VERSION 5.7 ;
  NOWIREEXTENSIONATPIN ON ;
  DIVIDERCHAR "/" ;
  BUSBITCHARS "[]" ;
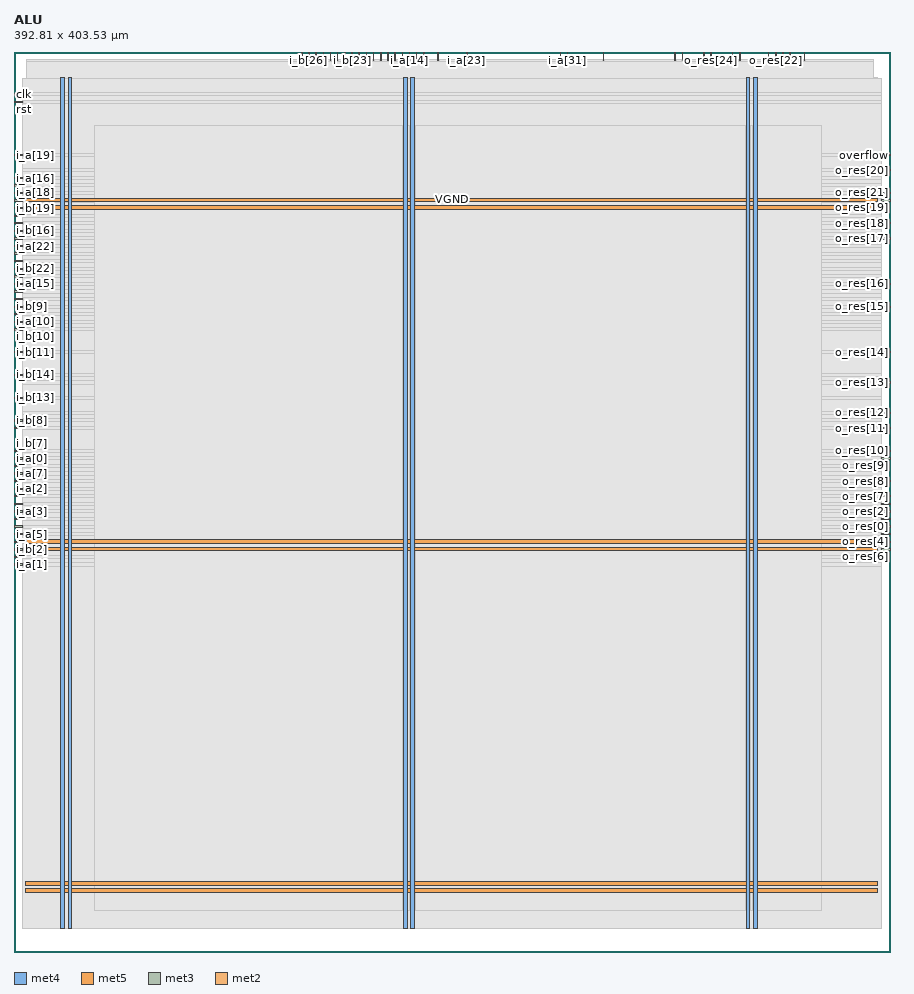
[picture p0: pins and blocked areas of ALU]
MACRO ALU
  CLASS BLOCK ;
  FOREIGN ALU ;
  ORIGIN 0.000 0.000 ;
  SIZE 392.810 BY 403.530 ;
  PIN VGND
    DIRECTION INOUT ;
    USE GROUND ;
    PORT
      LAYER met4 ;
        RECT 24.340 10.640 25.940 391.920 ;
    END
    PORT
      LAYER met4 ;
        RECT 177.940 10.640 179.540 391.920 ;
    END
    PORT
      LAYER met4 ;
        RECT 331.540 10.640 333.140 391.920 ;
    END
    PORT
      LAYER met5 ;
        RECT 5.280 30.030 387.100 31.630 ;
    END
    PORT
      LAYER met5 ;
        RECT 5.280 183.210 387.100 184.810 ;
    END
    PORT
      LAYER met5 ;
        RECT 5.280 336.390 387.100 337.990 ;
    END
  END VGND
  PIN VPWR
    DIRECTION INOUT ;
    USE POWER ;
    PORT
      LAYER met4 ;
        RECT 21.040 10.640 22.640 391.920 ;
    END
    PORT
      LAYER met4 ;
        RECT 174.640 10.640 176.240 391.920 ;
    END
    PORT
      LAYER met4 ;
        RECT 328.240 10.640 329.840 391.920 ;
    END
    PORT
      LAYER met5 ;
        RECT 5.280 26.730 387.100 28.330 ;
    END
    PORT
      LAYER met5 ;
        RECT 5.280 179.910 387.100 181.510 ;
    END
    PORT
      LAYER met5 ;
        RECT 5.280 333.090 387.100 334.690 ;
    END
  END VPWR
  PIN clk
    DIRECTION INPUT ;
    USE SIGNAL ;
    ANTENNAGATEAREA 1.286700 ;
    ANTENNADIFFAREA 0.434700 ;
    PORT
      LAYER met3 ;
        RECT 0.000 384.240 4.000 384.840 ;
    END
  END clk
  PIN i_a[0]
    DIRECTION INPUT ;
    USE SIGNAL ;
    ANTENNAGATEAREA 0.631200 ;
    ANTENNADIFFAREA 0.434700 ;
    PORT
      LAYER met3 ;
        RECT 0.000 221.040 4.000 221.640 ;
    END
  END i_a[0]
  PIN i_a[10]
    DIRECTION INPUT ;
    USE SIGNAL ;
    ANTENNAGATEAREA 0.631200 ;
    ANTENNADIFFAREA 0.434700 ;
    PORT
      LAYER met3 ;
        RECT 0.000 282.240 4.000 282.840 ;
    END
  END i_a[10]
  PIN i_a[11]
    DIRECTION INPUT ;
    USE SIGNAL ;
    ANTENNAGATEAREA 0.631200 ;
    ANTENNADIFFAREA 0.434700 ;
    PORT
      LAYER met2 ;
        RECT 128.890 399.530 129.170 403.530 ;
    END
  END i_a[11]
  PIN i_a[12]
    DIRECTION INPUT ;
    USE SIGNAL ;
    ANTENNAGATEAREA 0.631200 ;
    ANTENNADIFFAREA 0.434700 ;
    PORT
      LAYER met3 ;
        RECT 0.000 285.640 4.000 286.240 ;
    END
  END i_a[12]
  PIN i_a[13]
    DIRECTION INPUT ;
    USE SIGNAL ;
    ANTENNAGATEAREA 0.631200 ;
    ANTENNADIFFAREA 0.434700 ;
    PORT
      LAYER met2 ;
        RECT 135.330 399.530 135.610 403.530 ;
    END
  END i_a[13]
  PIN i_a[14]
    DIRECTION INPUT ;
    USE SIGNAL ;
    ANTENNAGATEAREA 0.631200 ;
    ANTENNADIFFAREA 0.434700 ;
    PORT
      LAYER met2 ;
        RECT 177.190 399.530 177.470 403.530 ;
    END
  END i_a[14]
  PIN i_a[15]
    DIRECTION INPUT ;
    USE SIGNAL ;
    ANTENNAGATEAREA 0.631200 ;
    ANTENNADIFFAREA 0.434700 ;
    PORT
      LAYER met3 ;
        RECT 0.000 299.240 4.000 299.840 ;
    END
  END i_a[15]
  PIN i_a[16]
    DIRECTION INPUT ;
    USE SIGNAL ;
    ANTENNAGATEAREA 0.631200 ;
    ANTENNADIFFAREA 0.434700 ;
    PORT
      LAYER met3 ;
        RECT 0.000 343.440 4.000 344.040 ;
    END
  END i_a[16]
  PIN i_a[17]
    DIRECTION INPUT ;
    USE SIGNAL ;
    ANTENNAGATEAREA 0.631200 ;
    ANTENNADIFFAREA 0.434700 ;
    PORT
      LAYER met3 ;
        RECT 0.000 329.840 4.000 330.440 ;
    END
  END i_a[17]
  PIN i_a[18]
    DIRECTION INPUT ;
    USE SIGNAL ;
    ANTENNAGATEAREA 0.631200 ;
    ANTENNADIFFAREA 0.434700 ;
    PORT
      LAYER met3 ;
        RECT 0.000 340.040 4.000 340.640 ;
    END
  END i_a[18]
  PIN i_a[19]
    DIRECTION INPUT ;
    USE SIGNAL ;
    ANTENNAGATEAREA 0.631200 ;
    ANTENNADIFFAREA 0.434700 ;
    PORT
      LAYER met3 ;
        RECT 0.000 357.040 4.000 357.640 ;
    END
  END i_a[19]
  PIN i_a[1]
    DIRECTION INPUT ;
    USE SIGNAL ;
    ANTENNAGATEAREA 0.631200 ;
    ANTENNADIFFAREA 0.434700 ;
    PORT
      LAYER met3 ;
        RECT 0.000 173.440 4.000 174.040 ;
    END
  END i_a[1]
  PIN i_a[20]
    DIRECTION INPUT ;
    USE SIGNAL ;
    ANTENNAGATEAREA 0.631200 ;
    ANTENNADIFFAREA 0.434700 ;
    PORT
      LAYER met3 ;
        RECT 0.000 346.840 4.000 347.440 ;
    END
  END i_a[20]
  PIN i_a[21]
    DIRECTION INPUT ;
    USE SIGNAL ;
    ANTENNAGATEAREA 0.631200 ;
    ANTENNADIFFAREA 0.434700 ;
    PORT
      LAYER met3 ;
        RECT 0.000 326.440 4.000 327.040 ;
    END
  END i_a[21]
  PIN i_a[22]
    DIRECTION INPUT ;
    USE SIGNAL ;
    ANTENNAGATEAREA 0.631200 ;
    ANTENNADIFFAREA 0.434700 ;
    PORT
      LAYER met3 ;
        RECT 0.000 316.240 4.000 316.840 ;
    END
  END i_a[22]
  PIN i_a[23]
    DIRECTION INPUT ;
    USE SIGNAL ;
    ANTENNAGATEAREA 0.631200 ;
    ANTENNADIFFAREA 0.434700 ;
    PORT
      LAYER met2 ;
        RECT 202.950 399.530 203.230 403.530 ;
    END
  END i_a[23]
  PIN i_a[24]
    DIRECTION INPUT ;
    USE SIGNAL ;
    ANTENNAGATEAREA 0.631200 ;
    ANTENNADIFFAREA 0.434700 ;
    PORT
      LAYER met2 ;
        RECT 190.070 399.530 190.350 403.530 ;
    END
  END i_a[24]
  PIN i_a[25]
    DIRECTION INPUT ;
    USE SIGNAL ;
    ANTENNAGATEAREA 0.631200 ;
    ANTENNADIFFAREA 0.434700 ;
    PORT
      LAYER met2 ;
        RECT 180.410 399.530 180.690 403.530 ;
    END
  END i_a[25]
  PIN i_a[26]
    DIRECTION INPUT ;
    USE SIGNAL ;
    ANTENNAGATEAREA 0.631200 ;
    ANTENNADIFFAREA 0.434700 ;
    PORT
      LAYER met2 ;
        RECT 183.630 399.530 183.910 403.530 ;
    END
  END i_a[26]
  PIN i_a[27]
    DIRECTION INPUT ;
    USE SIGNAL ;
    ANTENNAGATEAREA 0.631200 ;
    ANTENNADIFFAREA 0.434700 ;
    PORT
      LAYER met2 ;
        RECT 164.310 399.530 164.590 403.530 ;
    END
  END i_a[27]
  PIN i_a[28]
    DIRECTION INPUT ;
    USE SIGNAL ;
    ANTENNAGATEAREA 0.631200 ;
    ANTENNADIFFAREA 0.434700 ;
    PORT
      LAYER met2 ;
        RECT 173.970 399.530 174.250 403.530 ;
    END
  END i_a[28]
  PIN i_a[29]
    DIRECTION INPUT ;
    USE SIGNAL ;
    ANTENNAGATEAREA 0.631200 ;
    ANTENNADIFFAREA 0.434700 ;
    PORT
      LAYER met2 ;
        RECT 161.090 399.530 161.370 403.530 ;
    END
  END i_a[29]
  PIN i_a[2]
    DIRECTION INPUT ;
    USE SIGNAL ;
    ANTENNAGATEAREA 0.631200 ;
    ANTENNADIFFAREA 0.434700 ;
    PORT
      LAYER met3 ;
        RECT 0.000 207.440 4.000 208.040 ;
    END
  END i_a[2]
  PIN i_a[30]
    DIRECTION INPUT ;
    USE SIGNAL ;
    ANTENNAGATEAREA 0.631200 ;
    ANTENNADIFFAREA 0.434700 ;
    PORT
      LAYER met2 ;
        RECT 138.550 399.530 138.830 403.530 ;
    END
  END i_a[30]
  PIN i_a[31]
    DIRECTION INPUT ;
    USE SIGNAL ;
    ANTENNAGATEAREA 0.631200 ;
    ANTENNADIFFAREA 0.434700 ;
    PORT
      LAYER met2 ;
        RECT 248.030 399.530 248.310 403.530 ;
    END
  END i_a[31]
  PIN i_a[3]
    DIRECTION INPUT ;
    USE SIGNAL ;
    ANTENNAGATEAREA 0.631200 ;
    ANTENNADIFFAREA 0.434700 ;
    PORT
      LAYER met3 ;
        RECT 0.000 197.240 4.000 197.840 ;
    END
  END i_a[3]
  PIN i_a[4]
    DIRECTION INPUT ;
    USE SIGNAL ;
    ANTENNAGATEAREA 0.631200 ;
    ANTENNADIFFAREA 0.434700 ;
    PORT
      LAYER met3 ;
        RECT 0.000 183.640 4.000 184.240 ;
    END
  END i_a[4]
  PIN i_a[5]
    DIRECTION INPUT ;
    USE SIGNAL ;
    ANTENNAGATEAREA 0.631200 ;
    ANTENNADIFFAREA 0.434700 ;
    PORT
      LAYER met3 ;
        RECT 0.000 187.040 4.000 187.640 ;
    END
  END i_a[5]
  PIN i_a[6]
    DIRECTION INPUT ;
    USE SIGNAL ;
    ANTENNAGATEAREA 0.631200 ;
    ANTENNADIFFAREA 0.434700 ;
    PORT
      LAYER met3 ;
        RECT 0.000 193.840 4.000 194.440 ;
    END
  END i_a[6]
  PIN i_a[7]
    DIRECTION INPUT ;
    USE SIGNAL ;
    ANTENNAGATEAREA 0.631200 ;
    ANTENNADIFFAREA 0.434700 ;
    PORT
      LAYER met3 ;
        RECT 0.000 210.840 4.000 211.440 ;
    END
  END i_a[7]
  PIN i_a[8]
    DIRECTION INPUT ;
    USE SIGNAL ;
    ANTENNAGATEAREA 0.631200 ;
    ANTENNADIFFAREA 0.434700 ;
    PORT
      LAYER met3 ;
        RECT 0.000 234.640 4.000 235.240 ;
    END
  END i_a[8]
  PIN i_a[9]
    DIRECTION INPUT ;
    USE SIGNAL ;
    ANTENNAGATEAREA 0.631200 ;
    ANTENNADIFFAREA 0.434700 ;
    PORT
      LAYER met3 ;
        RECT 0.000 295.840 4.000 296.440 ;
    END
  END i_a[9]
  PIN i_b[0]
    DIRECTION INPUT ;
    USE SIGNAL ;
    ANTENNAGATEAREA 0.631200 ;
    ANTENNADIFFAREA 0.434700 ;
    PORT
      LAYER met3 ;
        RECT 0.000 217.640 4.000 218.240 ;
    END
  END i_b[0]
  PIN i_b[10]
    DIRECTION INPUT ;
    USE SIGNAL ;
    ANTENNAGATEAREA 0.631200 ;
    ANTENNADIFFAREA 0.434700 ;
    PORT
      LAYER met3 ;
        RECT 0.000 278.840 4.000 279.440 ;
    END
  END i_b[10]
  PIN i_b[11]
    DIRECTION INPUT ;
    USE SIGNAL ;
    ANTENNAGATEAREA 0.631200 ;
    ANTENNADIFFAREA 0.434700 ;
    PORT
      LAYER met3 ;
        RECT 0.000 268.640 4.000 269.240 ;
    END
  END i_b[11]
  PIN i_b[12]
    DIRECTION INPUT ;
    USE SIGNAL ;
    ANTENNAGATEAREA 0.631200 ;
    ANTENNADIFFAREA 0.434700 ;
    PORT
      LAYER met3 ;
        RECT 0.000 292.440 4.000 293.040 ;
    END
  END i_b[12]
  PIN i_b[13]
    DIRECTION INPUT ;
    USE SIGNAL ;
    ANTENNAGATEAREA 0.631200 ;
    ANTENNADIFFAREA 0.434700 ;
    PORT
      LAYER met3 ;
        RECT 0.000 248.240 4.000 248.840 ;
    END
  END i_b[13]
  PIN i_b[14]
    DIRECTION INPUT ;
    USE SIGNAL ;
    ANTENNAGATEAREA 0.631200 ;
    ANTENNADIFFAREA 0.434700 ;
    PORT
      LAYER met3 ;
        RECT 0.000 258.440 4.000 259.040 ;
    END
  END i_b[14]
  PIN i_b[15]
    DIRECTION INPUT ;
    USE SIGNAL ;
    ANTENNAGATEAREA 0.631200 ;
    ANTENNADIFFAREA 0.434700 ;
    PORT
      LAYER met3 ;
        RECT 0.000 302.640 4.000 303.240 ;
    END
  END i_b[15]
  PIN i_b[16]
    DIRECTION INPUT ;
    USE SIGNAL ;
    ANTENNAGATEAREA 0.631200 ;
    ANTENNADIFFAREA 0.434700 ;
    PORT
      LAYER met3 ;
        RECT 0.000 323.040 4.000 323.640 ;
    END
  END i_b[16]
  PIN i_b[17]
    DIRECTION INPUT ;
    USE SIGNAL ;
    ANTENNAGATEAREA 0.631200 ;
    ANTENNADIFFAREA 0.434700 ;
    PORT
      LAYER met3 ;
        RECT 0.000 312.840 4.000 313.440 ;
    END
  END i_b[17]
  PIN i_b[18]
    DIRECTION INPUT ;
    USE SIGNAL ;
    ANTENNAGATEAREA 0.631200 ;
    ANTENNADIFFAREA 0.434700 ;
    PORT
      LAYER met3 ;
        RECT 0.000 319.640 4.000 320.240 ;
    END
  END i_b[18]
  PIN i_b[19]
    DIRECTION INPUT ;
    USE SIGNAL ;
    ANTENNAGATEAREA 0.631200 ;
    ANTENNADIFFAREA 0.434700 ;
    PORT
      LAYER met3 ;
        RECT 0.000 333.240 4.000 333.840 ;
    END
  END i_b[19]
  PIN i_b[1]
    DIRECTION INPUT ;
    USE SIGNAL ;
    ANTENNAGATEAREA 0.631200 ;
    ANTENNADIFFAREA 0.434700 ;
    PORT
      LAYER met3 ;
        RECT 0.000 200.640 4.000 201.240 ;
    END
  END i_b[1]
  PIN i_b[20]
    DIRECTION INPUT ;
    USE SIGNAL ;
    ANTENNAGATEAREA 0.631200 ;
    ANTENNADIFFAREA 0.434700 ;
    PORT
      LAYER met3 ;
        RECT 0.000 336.640 4.000 337.240 ;
    END
  END i_b[20]
  PIN i_b[21]
    DIRECTION INPUT ;
    USE SIGNAL ;
    ANTENNAGATEAREA 0.631200 ;
    ANTENNADIFFAREA 0.434700 ;
    PORT
      LAYER met3 ;
        RECT 0.000 309.440 4.000 310.040 ;
    END
  END i_b[21]
  PIN i_b[22]
    DIRECTION INPUT ;
    USE SIGNAL ;
    ANTENNAGATEAREA 0.631200 ;
    ANTENNADIFFAREA 0.434700 ;
    PORT
      LAYER met3 ;
        RECT 0.000 306.040 4.000 306.640 ;
    END
  END i_b[22]
  PIN i_b[23]
    DIRECTION INPUT ;
    USE SIGNAL ;
    ANTENNAGATEAREA 0.631200 ;
    ANTENNADIFFAREA 0.434700 ;
    PORT
      LAYER met2 ;
        RECT 151.430 399.530 151.710 403.530 ;
    END
  END i_b[23]
  PIN i_b[24]
    DIRECTION INPUT ;
    USE SIGNAL ;
    ANTENNAGATEAREA 0.631200 ;
    ANTENNADIFFAREA 0.434700 ;
    PORT
      LAYER met2 ;
        RECT 144.990 399.530 145.270 403.530 ;
    END
  END i_b[24]
  PIN i_b[25]
    DIRECTION INPUT ;
    USE SIGNAL ;
    ANTENNAGATEAREA 0.631200 ;
    ANTENNADIFFAREA 0.434700 ;
    PORT
      LAYER met2 ;
        RECT 141.770 399.530 142.050 403.530 ;
    END
  END i_b[25]
  PIN i_b[26]
    DIRECTION INPUT ;
    USE SIGNAL ;
    ANTENNAGATEAREA 0.631200 ;
    ANTENNADIFFAREA 0.434700 ;
    PORT
      LAYER met2 ;
        RECT 132.110 399.530 132.390 403.530 ;
    END
  END i_b[26]
  PIN i_b[27]
    DIRECTION INPUT ;
    USE SIGNAL ;
    ANTENNAGATEAREA 0.631200 ;
    ANTENNADIFFAREA 0.434700 ;
    PORT
      LAYER met2 ;
        RECT 154.650 399.530 154.930 403.530 ;
    END
  END i_b[27]
  PIN i_b[28]
    DIRECTION INPUT ;
    USE SIGNAL ;
    ANTENNAGATEAREA 0.631200 ;
    ANTENNADIFFAREA 0.434700 ;
    PORT
      LAYER met2 ;
        RECT 167.530 399.530 167.810 403.530 ;
    END
  END i_b[28]
  PIN i_b[29]
    DIRECTION INPUT ;
    USE SIGNAL ;
    ANTENNAGATEAREA 0.631200 ;
    ANTENNADIFFAREA 0.434700 ;
    PORT
      LAYER met2 ;
        RECT 148.210 399.530 148.490 403.530 ;
    END
  END i_b[29]
  PIN i_b[2]
    DIRECTION INPUT ;
    USE SIGNAL ;
    ANTENNAGATEAREA 0.631200 ;
    ANTENNADIFFAREA 0.434700 ;
    PORT
      LAYER met3 ;
        RECT 0.000 180.240 4.000 180.840 ;
    END
  END i_b[2]
  PIN i_b[30]
    DIRECTION INPUT ;
    USE SIGNAL ;
    ANTENNAGATEAREA 0.631200 ;
    ANTENNADIFFAREA 0.434700 ;
    PORT
      LAYER met2 ;
        RECT 157.870 399.530 158.150 403.530 ;
    END
  END i_b[30]
  PIN i_b[31]
    DIRECTION INPUT ;
    USE SIGNAL ;
    ANTENNAGATEAREA 0.631200 ;
    ANTENNADIFFAREA 0.434700 ;
    PORT
      LAYER met2 ;
        RECT 244.810 399.530 245.090 403.530 ;
    END
  END i_b[31]
  PIN i_b[3]
    DIRECTION INPUT ;
    USE SIGNAL ;
    ANTENNAGATEAREA 0.631200 ;
    ANTENNADIFFAREA 0.434700 ;
    PORT
      LAYER met3 ;
        RECT 0.000 176.840 4.000 177.440 ;
    END
  END i_b[3]
  PIN i_b[4]
    DIRECTION INPUT ;
    USE SIGNAL ;
    ANTENNAGATEAREA 0.631200 ;
    ANTENNADIFFAREA 0.434700 ;
    PORT
      LAYER met3 ;
        RECT 0.000 204.040 4.000 204.640 ;
    END
  END i_b[4]
  PIN i_b[5]
    DIRECTION INPUT ;
    USE SIGNAL ;
    ANTENNAGATEAREA 0.631200 ;
    ANTENNADIFFAREA 0.434700 ;
    PORT
      LAYER met3 ;
        RECT 0.000 190.440 4.000 191.040 ;
    END
  END i_b[5]
  PIN i_b[6]
    DIRECTION INPUT ;
    USE SIGNAL ;
    ANTENNAGATEAREA 0.631200 ;
    ANTENNADIFFAREA 0.434700 ;
    PORT
      LAYER met3 ;
        RECT 0.000 214.240 4.000 214.840 ;
    END
  END i_b[6]
  PIN i_b[7]
    DIRECTION INPUT ;
    USE SIGNAL ;
    ANTENNAGATEAREA 0.631200 ;
    ANTENNADIFFAREA 0.434700 ;
    PORT
      LAYER met3 ;
        RECT 0.000 224.440 4.000 225.040 ;
    END
  END i_b[7]
  PIN i_b[8]
    DIRECTION INPUT ;
    USE SIGNAL ;
    ANTENNAGATEAREA 0.631200 ;
    ANTENNADIFFAREA 0.434700 ;
    PORT
      LAYER met3 ;
        RECT 0.000 238.040 4.000 238.640 ;
    END
  END i_b[8]
  PIN i_b[9]
    DIRECTION INPUT ;
    USE SIGNAL ;
    ANTENNAGATEAREA 0.631200 ;
    ANTENNADIFFAREA 0.434700 ;
    PORT
      LAYER met3 ;
        RECT 0.000 289.040 4.000 289.640 ;
    END
  END i_b[9]
  PIN i_vld
    DIRECTION INPUT ;
    USE SIGNAL ;
    ANTENNAGATEAREA 0.631200 ;
    ANTENNADIFFAREA 0.434700 ;
    PORT
      LAYER met2 ;
        RECT 170.750 399.530 171.030 403.530 ;
    END
  END i_vld
  PIN o_res[0]
    DIRECTION OUTPUT ;
    USE SIGNAL ;
    ANTENNADIFFAREA 0.445500 ;
    PORT
      LAYER met3 ;
        RECT 388.810 190.440 392.810 191.040 ;
    END
  END o_res[0]
  PIN o_res[10]
    DIRECTION OUTPUT ;
    USE SIGNAL ;
    ANTENNADIFFAREA 0.445500 ;
    PORT
      LAYER met3 ;
        RECT 388.810 224.440 392.810 225.040 ;
    END
  END o_res[10]
  PIN o_res[11]
    DIRECTION OUTPUT ;
    USE SIGNAL ;
    ANTENNADIFFAREA 0.445500 ;
    PORT
      LAYER met3 ;
        RECT 388.810 234.640 392.810 235.240 ;
    END
  END o_res[11]
  PIN o_res[12]
    DIRECTION OUTPUT ;
    USE SIGNAL ;
    ANTENNADIFFAREA 0.445500 ;
    PORT
      LAYER met3 ;
        RECT 388.810 241.440 392.810 242.040 ;
    END
  END o_res[12]
  PIN o_res[13]
    DIRECTION OUTPUT ;
    USE SIGNAL ;
    ANTENNADIFFAREA 0.445500 ;
    PORT
      LAYER met3 ;
        RECT 388.810 255.040 392.810 255.640 ;
    END
  END o_res[13]
  PIN o_res[14]
    DIRECTION OUTPUT ;
    USE SIGNAL ;
    ANTENNADIFFAREA 0.445500 ;
    PORT
      LAYER met3 ;
        RECT 388.810 268.640 392.810 269.240 ;
    END
  END o_res[14]
  PIN o_res[15]
    DIRECTION OUTPUT ;
    USE SIGNAL ;
    ANTENNADIFFAREA 0.445500 ;
    PORT
      LAYER met3 ;
        RECT 388.810 289.040 392.810 289.640 ;
    END
  END o_res[15]
  PIN o_res[16]
    DIRECTION OUTPUT ;
    USE SIGNAL ;
    ANTENNADIFFAREA 0.445500 ;
    PORT
      LAYER met3 ;
        RECT 388.810 299.240 392.810 299.840 ;
    END
  END o_res[16]
  PIN o_res[17]
    DIRECTION OUTPUT ;
    USE SIGNAL ;
    ANTENNADIFFAREA 0.445500 ;
    PORT
      LAYER met3 ;
        RECT 388.810 319.640 392.810 320.240 ;
    END
  END o_res[17]
  PIN o_res[18]
    DIRECTION OUTPUT ;
    USE SIGNAL ;
    ANTENNADIFFAREA 0.445500 ;
    PORT
      LAYER met3 ;
        RECT 388.810 326.440 392.810 327.040 ;
    END
  END o_res[18]
  PIN o_res[19]
    DIRECTION OUTPUT ;
    USE SIGNAL ;
    ANTENNADIFFAREA 0.445500 ;
    PORT
      LAYER met3 ;
        RECT 388.810 336.640 392.810 337.240 ;
    END
  END o_res[19]
  PIN o_res[1]
    DIRECTION OUTPUT ;
    USE SIGNAL ;
    ANTENNADIFFAREA 0.445500 ;
    PORT
      LAYER met3 ;
        RECT 388.810 183.640 392.810 184.240 ;
    END
  END o_res[1]
  PIN o_res[20]
    DIRECTION OUTPUT ;
    USE SIGNAL ;
    ANTENNADIFFAREA 0.445500 ;
    PORT
      LAYER met3 ;
        RECT 388.810 350.240 392.810 350.840 ;
    END
  END o_res[20]
  PIN o_res[21]
    DIRECTION OUTPUT ;
    USE SIGNAL ;
    ANTENNADIFFAREA 0.445500 ;
    PORT
      LAYER met3 ;
        RECT 388.810 340.040 392.810 340.640 ;
    END
  END o_res[21]
  PIN o_res[22]
    DIRECTION OUTPUT ;
    USE SIGNAL ;
    ANTENNADIFFAREA 0.445500 ;
    PORT
      LAYER met2 ;
        RECT 341.410 399.530 341.690 403.530 ;
    END
  END o_res[22]
  PIN o_res[23]
    DIRECTION OUTPUT ;
    USE SIGNAL ;
    ANTENNADIFFAREA 0.445500 ;
    PORT
      LAYER met2 ;
        RECT 325.310 399.530 325.590 403.530 ;
    END
  END o_res[23]
  PIN o_res[24]
    DIRECTION OUTPUT ;
    USE SIGNAL ;
    ANTENNADIFFAREA 0.445500 ;
    PORT
      LAYER met2 ;
        RECT 312.430 399.530 312.710 403.530 ;
    END
  END o_res[24]
  PIN o_res[25]
    DIRECTION OUTPUT ;
    USE SIGNAL ;
    ANTENNADIFFAREA 0.445500 ;
    PORT
      LAYER met2 ;
        RECT 338.190 399.530 338.470 403.530 ;
    END
  END o_res[25]
  PIN o_res[26]
    DIRECTION OUTPUT ;
    USE SIGNAL ;
    ANTENNADIFFAREA 0.445500 ;
    PORT
      LAYER met2 ;
        RECT 296.330 399.530 296.610 403.530 ;
    END
  END o_res[26]
  PIN o_res[27]
    DIRECTION OUTPUT ;
    USE SIGNAL ;
    ANTENNADIFFAREA 0.445500 ;
    PORT
      LAYER met2 ;
        RECT 347.850 399.530 348.130 403.530 ;
    END
  END o_res[27]
  PIN o_res[28]
    DIRECTION OUTPUT ;
    USE SIGNAL ;
    ANTENNADIFFAREA 0.445500 ;
    PORT
      LAYER met2 ;
        RECT 344.630 399.530 344.910 403.530 ;
    END
  END o_res[28]
  PIN o_res[29]
    DIRECTION OUTPUT ;
    USE SIGNAL ;
    ANTENNADIFFAREA 0.445500 ;
    PORT
      LAYER met2 ;
        RECT 309.210 399.530 309.490 403.530 ;
    END
  END o_res[29]
  PIN o_res[2]
    DIRECTION OUTPUT ;
    USE SIGNAL ;
    ANTENNADIFFAREA 0.445500 ;
    PORT
      LAYER met3 ;
        RECT 388.810 193.840 392.810 194.440 ;
    END
  END o_res[2]
  PIN o_res[30]
    DIRECTION OUTPUT ;
    USE SIGNAL ;
    ANTENNADIFFAREA 0.445500 ;
    PORT
      LAYER met2 ;
        RECT 322.090 399.530 322.370 403.530 ;
    END
  END o_res[30]
  PIN o_res[31]
    DIRECTION OUTPUT ;
    USE SIGNAL ;
    ANTENNADIFFAREA 0.445500 ;
    PORT
      LAYER met2 ;
        RECT 299.550 399.530 299.830 403.530 ;
    END
  END o_res[31]
  PIN o_res[3]
    DIRECTION OUTPUT ;
    USE SIGNAL ;
    ANTENNADIFFAREA 0.445500 ;
    PORT
      LAYER met3 ;
        RECT 388.810 197.240 392.810 197.840 ;
    END
  END o_res[3]
  PIN o_res[4]
    DIRECTION OUTPUT ;
    USE SIGNAL ;
    ANTENNADIFFAREA 0.445500 ;
    PORT
      LAYER met3 ;
        RECT 388.810 187.040 392.810 187.640 ;
    END
  END o_res[4]
  PIN o_res[5]
    DIRECTION OUTPUT ;
    USE SIGNAL ;
    ANTENNADIFFAREA 0.445500 ;
    PORT
      LAYER met3 ;
        RECT 388.810 200.640 392.810 201.240 ;
    END
  END o_res[5]
  PIN o_res[6]
    DIRECTION OUTPUT ;
    USE SIGNAL ;
    ANTENNADIFFAREA 0.445500 ;
    PORT
      LAYER met3 ;
        RECT 388.810 180.240 392.810 180.840 ;
    END
  END o_res[6]
  PIN o_res[7]
    DIRECTION OUTPUT ;
    USE SIGNAL ;
    ANTENNADIFFAREA 0.445500 ;
    PORT
      LAYER met3 ;
        RECT 388.810 204.040 392.810 204.640 ;
    END
  END o_res[7]
  PIN o_res[8]
    DIRECTION OUTPUT ;
    USE SIGNAL ;
    ANTENNADIFFAREA 0.445500 ;
    PORT
      LAYER met3 ;
        RECT 388.810 210.840 392.810 211.440 ;
    END
  END o_res[8]
  PIN o_res[9]
    DIRECTION OUTPUT ;
    USE SIGNAL ;
    ANTENNADIFFAREA 0.445500 ;
    PORT
      LAYER met3 ;
        RECT 388.810 221.040 392.810 221.640 ;
    END
  END o_res[9]
  PIN o_res_vld
    DIRECTION OUTPUT ;
    USE SIGNAL ;
    ANTENNADIFFAREA 0.445500 ;
    PORT
      LAYER met2 ;
        RECT 264.130 399.530 264.410 403.530 ;
    END
  END o_res_vld
  PIN opcode
    DIRECTION INPUT ;
    USE SIGNAL ;
    ANTENNAGATEAREA 0.631200 ;
    ANTENNADIFFAREA 0.434700 ;
    PORT
      LAYER met2 ;
        RECT 354.290 399.530 354.570 403.530 ;
    END
  END opcode
  PIN overflow
    DIRECTION OUTPUT ;
    USE SIGNAL ;
    ANTENNADIFFAREA 0.445500 ;
    PORT
      LAYER met3 ;
        RECT 388.810 357.040 392.810 357.640 ;
    END
  END overflow
  PIN rst
    DIRECTION INPUT ;
    USE SIGNAL ;
    ANTENNAGATEAREA 0.647700 ;
    ANTENNADIFFAREA 0.434700 ;
    PORT
      LAYER met3 ;
        RECT 0.000 380.840 4.000 381.440 ;
    END
  END rst
  OBS
      LAYER nwell ;
        RECT 5.330 10.795 387.050 391.765 ;
      LAYER li1 ;
        RECT 5.520 10.795 386.860 391.765 ;
      LAYER met1 ;
        RECT 5.520 10.640 387.160 392.320 ;
      LAYER met2 ;
        RECT 5.610 399.250 128.610 400.250 ;
        RECT 129.450 399.250 131.830 400.250 ;
        RECT 132.670 399.250 135.050 400.250 ;
        RECT 135.890 399.250 138.270 400.250 ;
        RECT 139.110 399.250 141.490 400.250 ;
        RECT 142.330 399.250 144.710 400.250 ;
        RECT 145.550 399.250 147.930 400.250 ;
        RECT 148.770 399.250 151.150 400.250 ;
        RECT 151.990 399.250 154.370 400.250 ;
        RECT 155.210 399.250 157.590 400.250 ;
        RECT 158.430 399.250 160.810 400.250 ;
        RECT 161.650 399.250 164.030 400.250 ;
        RECT 164.870 399.250 167.250 400.250 ;
        RECT 168.090 399.250 170.470 400.250 ;
        RECT 171.310 399.250 173.690 400.250 ;
        RECT 174.530 399.250 176.910 400.250 ;
        RECT 177.750 399.250 180.130 400.250 ;
        RECT 180.970 399.250 183.350 400.250 ;
        RECT 184.190 399.250 189.790 400.250 ;
        RECT 190.630 399.250 202.670 400.250 ;
        RECT 203.510 399.250 244.530 400.250 ;
        RECT 245.370 399.250 247.750 400.250 ;
        RECT 248.590 399.250 263.850 400.250 ;
        RECT 264.690 399.250 296.050 400.250 ;
        RECT 296.890 399.250 299.270 400.250 ;
        RECT 300.110 399.250 308.930 400.250 ;
        RECT 309.770 399.250 312.150 400.250 ;
        RECT 312.990 399.250 321.810 400.250 ;
        RECT 322.650 399.250 325.030 400.250 ;
        RECT 325.870 399.250 337.910 400.250 ;
        RECT 338.750 399.250 341.130 400.250 ;
        RECT 341.970 399.250 344.350 400.250 ;
        RECT 345.190 399.250 347.570 400.250 ;
        RECT 348.410 399.250 354.010 400.250 ;
        RECT 354.850 399.250 385.390 400.250 ;
        RECT 5.610 10.695 385.390 399.250 ;
      LAYER met3 ;
        RECT 4.000 385.240 388.810 391.845 ;
        RECT 4.400 383.840 388.810 385.240 ;
        RECT 4.000 381.840 388.810 383.840 ;
        RECT 4.400 380.440 388.810 381.840 ;
        RECT 4.000 358.040 388.810 380.440 ;
        RECT 4.400 356.640 388.410 358.040 ;
        RECT 4.000 351.240 388.810 356.640 ;
        RECT 4.000 349.840 388.410 351.240 ;
        RECT 4.000 347.840 388.810 349.840 ;
        RECT 4.400 346.440 388.810 347.840 ;
        RECT 4.000 344.440 388.810 346.440 ;
        RECT 4.400 343.040 388.810 344.440 ;
        RECT 4.000 341.040 388.810 343.040 ;
        RECT 4.400 339.640 388.410 341.040 ;
        RECT 4.000 337.640 388.810 339.640 ;
        RECT 4.400 336.240 388.410 337.640 ;
        RECT 4.000 334.240 388.810 336.240 ;
        RECT 4.400 332.840 388.810 334.240 ;
        RECT 4.000 330.840 388.810 332.840 ;
        RECT 4.400 329.440 388.810 330.840 ;
        RECT 4.000 327.440 388.810 329.440 ;
        RECT 4.400 326.040 388.410 327.440 ;
        RECT 4.000 324.040 388.810 326.040 ;
        RECT 4.400 322.640 388.810 324.040 ;
        RECT 4.000 320.640 388.810 322.640 ;
        RECT 4.400 319.240 388.410 320.640 ;
        RECT 4.000 317.240 388.810 319.240 ;
        RECT 4.400 315.840 388.810 317.240 ;
        RECT 4.000 313.840 388.810 315.840 ;
        RECT 4.400 312.440 388.810 313.840 ;
        RECT 4.000 310.440 388.810 312.440 ;
        RECT 4.400 309.040 388.810 310.440 ;
        RECT 4.000 307.040 388.810 309.040 ;
        RECT 4.400 305.640 388.810 307.040 ;
        RECT 4.000 303.640 388.810 305.640 ;
        RECT 4.400 302.240 388.810 303.640 ;
        RECT 4.000 300.240 388.810 302.240 ;
        RECT 4.400 298.840 388.410 300.240 ;
        RECT 4.000 296.840 388.810 298.840 ;
        RECT 4.400 295.440 388.810 296.840 ;
        RECT 4.000 293.440 388.810 295.440 ;
        RECT 4.400 292.040 388.810 293.440 ;
        RECT 4.000 290.040 388.810 292.040 ;
        RECT 4.400 288.640 388.410 290.040 ;
        RECT 4.000 286.640 388.810 288.640 ;
        RECT 4.400 285.240 388.810 286.640 ;
        RECT 4.000 283.240 388.810 285.240 ;
        RECT 4.400 281.840 388.810 283.240 ;
        RECT 4.000 279.840 388.810 281.840 ;
        RECT 4.400 278.440 388.810 279.840 ;
        RECT 4.000 269.640 388.810 278.440 ;
        RECT 4.400 268.240 388.410 269.640 ;
        RECT 4.000 259.440 388.810 268.240 ;
        RECT 4.400 258.040 388.810 259.440 ;
        RECT 4.000 256.040 388.810 258.040 ;
        RECT 4.000 254.640 388.410 256.040 ;
        RECT 4.000 249.240 388.810 254.640 ;
        RECT 4.400 247.840 388.810 249.240 ;
        RECT 4.000 242.440 388.810 247.840 ;
        RECT 4.000 241.040 388.410 242.440 ;
        RECT 4.000 239.040 388.810 241.040 ;
        RECT 4.400 237.640 388.810 239.040 ;
        RECT 4.000 235.640 388.810 237.640 ;
        RECT 4.400 234.240 388.410 235.640 ;
        RECT 4.000 225.440 388.810 234.240 ;
        RECT 4.400 224.040 388.410 225.440 ;
        RECT 4.000 222.040 388.810 224.040 ;
        RECT 4.400 220.640 388.410 222.040 ;
        RECT 4.000 218.640 388.810 220.640 ;
        RECT 4.400 217.240 388.810 218.640 ;
        RECT 4.000 215.240 388.810 217.240 ;
        RECT 4.400 213.840 388.810 215.240 ;
        RECT 4.000 211.840 388.810 213.840 ;
        RECT 4.400 210.440 388.410 211.840 ;
        RECT 4.000 208.440 388.810 210.440 ;
        RECT 4.400 207.040 388.810 208.440 ;
        RECT 4.000 205.040 388.810 207.040 ;
        RECT 4.400 203.640 388.410 205.040 ;
        RECT 4.000 201.640 388.810 203.640 ;
        RECT 4.400 200.240 388.410 201.640 ;
        RECT 4.000 198.240 388.810 200.240 ;
        RECT 4.400 196.840 388.410 198.240 ;
        RECT 4.000 194.840 388.810 196.840 ;
        RECT 4.400 193.440 388.410 194.840 ;
        RECT 4.000 191.440 388.810 193.440 ;
        RECT 4.400 190.040 388.410 191.440 ;
        RECT 4.000 188.040 388.810 190.040 ;
        RECT 4.400 186.640 388.410 188.040 ;
        RECT 4.000 184.640 388.810 186.640 ;
        RECT 4.400 183.240 388.410 184.640 ;
        RECT 4.000 181.240 388.810 183.240 ;
        RECT 4.400 179.840 388.410 181.240 ;
        RECT 4.000 177.840 388.810 179.840 ;
        RECT 4.400 176.440 388.810 177.840 ;
        RECT 4.000 174.440 388.810 176.440 ;
        RECT 4.400 173.040 388.810 174.440 ;
        RECT 4.000 10.715 388.810 173.040 ;
      LAYER met4 ;
        RECT 36.175 18.535 174.240 370.425 ;
        RECT 176.640 18.535 177.540 370.425 ;
        RECT 179.940 18.535 327.840 370.425 ;
        RECT 330.240 18.535 331.140 370.425 ;
        RECT 333.540 18.535 362.185 370.425 ;
  END
END ALU
END LIBRARY

